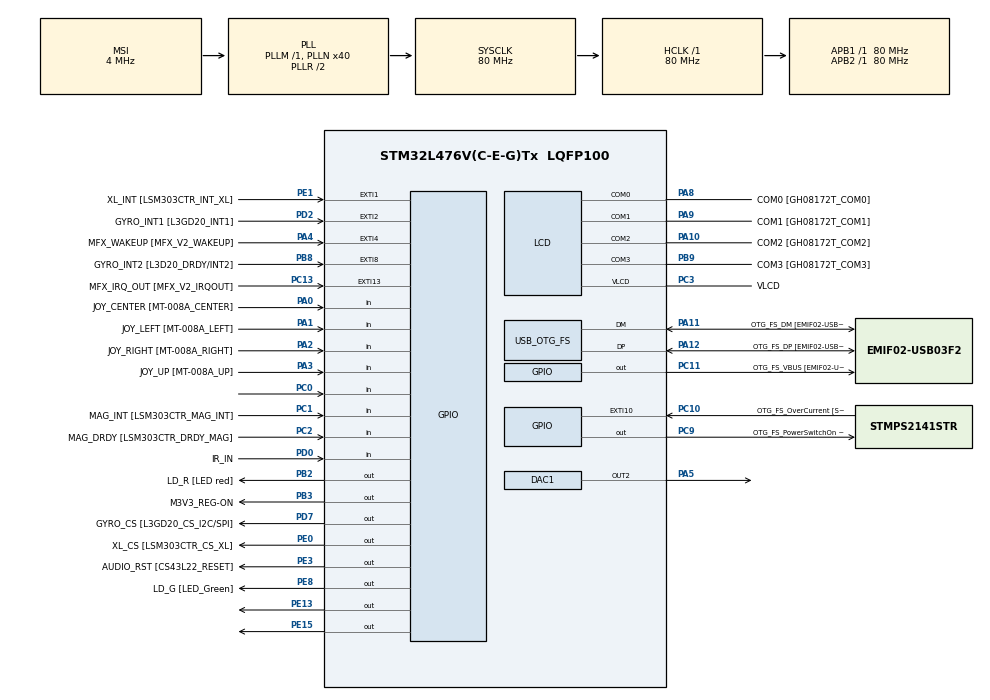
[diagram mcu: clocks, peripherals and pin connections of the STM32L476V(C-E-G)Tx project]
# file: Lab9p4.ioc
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DAC1.DAC_Channel-DAC_OUT2=DAC_CHANNEL_2
Mcu.Family=STM32L4
Mcu.Name=STM32L476V(C-E-G)Tx
Mcu.Package=LQFP100
NVIC.LCD_IRQn=true\:0\:0\:false\:false\:true\:true\:false\:true
NVIC.OTG_FS_IRQn=true\:0\:0\:false\:false\:true\:true\:true\:true
NVIC.PriorityGroup=NVIC_PRIORITYGROUP_4
NVIC.TIM1_UP_TIM16_IRQn=true\:0\:0\:false\:false\:true\:true\:true\:true
NVIC.TIM6_DAC_IRQn=true\:0\:0\:false\:false\:true\:true\:true\:true
NVIC.TIM7_IRQn=true\:0\:0\:false\:false\:true\:true\:true\:true
PA0.GPIO_Label=JOY_CENTER [MT-008A_CENTER]
PA0.GPIO_Mode=GPIO_MODE_INPUT
PA0.GPIO_PuPd=GPIO_PULLDOWN
PA0.Signal=GPIO_Input
PA1.GPIO_Label=JOY_LEFT [MT-008A_LEFT]
PA1.GPIO_Mode=GPIO_MODE_INPUT
PA1.GPIO_PuPd=GPIO_PULLDOWN
PA1.Signal=GPIO_Input
PA10.GPIO_Label=COM2 [GH08172T_COM2]
PA10.GPIO_Mode=GPIO_MODE_AF_PP
PA10.GPIO_PuPd=GPIO_NOPULL
PA10.GPIO_Speed=GPIO_SPEED_FREQ_LOW
PA10.Mode=1/4 Duty Cycle
PA10.Signal=LCD_COM2
PA11.GPIO_Label=OTG_FS_DM [EMIF02-USB03F2_D-out]
PA11.GPIO_Mode=GPIO_MODE_AF_PP
PA11.GPIO_PuPd=GPIO_NOPULL
PA11.GPIO_Speed=GPIO_SPEED_FREQ_VERY_HIGH
PA11.Mode=Host_Only
PA11.Signal=USB_OTG_FS_DM
PA12.GPIO_Label=OTG_FS_DP [EMIF02-USB03F2_D+out]
PA12.GPIO_Mode=GPIO_MODE_AF_PP
PA12.GPIO_PuPd=GPIO_NOPULL
PA12.GPIO_Speed=GPIO_SPEED_FREQ_VERY_HIGH
PA12.Mode=Host_Only
PA12.Signal=USB_OTG_FS_DP
PA13\ (JTMS-SWDIO).GPIO_Label=SWDIO
PA13\ (JTMS-SWDIO).Mode=Serial_Wire
PA13\ (JTMS-SWDIO).Signal=SYS_JTMS-SWDIO
PA14\ (JTCK-SWCLK).GPIO_Label=SWCLK
PA14\ (JTCK-SWCLK).Mode=Serial_Wire
PA14\ (JTCK-SWCLK).Signal=SYS_JTCK-SWCLK
PA15\ (JTDI).GPIO_Label=SEG10 [GH08172T_SEG10]
PA15\ (JTDI).GPIO_Mode=GPIO_MODE_AF_PP
PA15\ (JTDI).GPIO_PuPd=GPIO_NOPULL
PA15\ (JTDI).GPIO_Speed=GPIO_SPEED_FREQ_LOW
PA15\ (JTDI).Signal=LCD_SEG17
PA2.GPIO_Label=JOY_RIGHT [MT-008A_RIGHT]
PA2.GPIO_Mode=GPIO_MODE_INPUT
PA2.GPIO_PuPd=GPIO_PULLDOWN
PA2.Signal=GPIO_Input
PA3.GPIO_Label=JOY_UP [MT-008A_UP]
PA3.GPIO_Mode=GPIO_MODE_INPUT
PA3.GPIO_PuPd=GPIO_PULLDOWN
PA3.Signal=GPIO_Input
PA4.GPIO_Label=MFX_WAKEUP [MFX_V2_WAKEUP]
PA4.GPIO_ModeDefaultEXTI=GPIO_MODE_EVT_RISING
PA4.GPIO_PuPd=GPIO_NOPULL
PA4.Signal=GPXTI4
PA5.Signal=COMP_DAC12_group
PA6.GPIO_Label=SEG23 [GH08172T_SEG23]
PA6.GPIO_Mode=GPIO_MODE_AF_PP
PA6.GPIO_PuPd=GPIO_NOPULL
PA6.GPIO_Speed=GPIO_SPEED_FREQ_LOW
PA6.Signal=LCD_SEG3
PA7.GPIO_Label=SEG0 [GH08172T_SEG0]
PA7.GPIO_Mode=GPIO_MODE_AF_PP
PA7.GPIO_PuPd=GPIO_NOPULL
PA7.GPIO_Speed=GPIO_SPEED_FREQ_LOW
PA7.Signal=LCD_SEG4
PA8.GPIO_Label=COM0 [GH08172T_COM0]
PA8.GPIO_Mode=GPIO_MODE_AF_PP
PA8.GPIO_PuPd=GPIO_NOPULL
PA8.GPIO_Speed=GPIO_SPEED_FREQ_LOW
PA8.Mode=1/4 Duty Cycle
PA8.Signal=LCD_COM0
PA9.GPIO_Label=COM1 [GH08172T_COM1]
PA9.GPIO_Mode=GPIO_MODE_AF_PP
PA9.GPIO_PuPd=GPIO_NOPULL
PA9.GPIO_Speed=GPIO_SPEED_FREQ_LOW
PA9.Mode=1/4 Duty Cycle
PA9.Signal=LCD_COM1
PB0.GPIO_Label=SEG21 [GH08172T_SEG21]
PB0.GPIO_Mode=GPIO_MODE_AF_PP
PB0.GPIO_PuPd=GPIO_NOPULL
PB0.GPIO_Speed=GPIO_SPEED_FREQ_LOW
PB0.Signal=LCD_SEG5
PB1.GPIO_Label=SEG2 [GH08172T_SEG2]
PB1.GPIO_Mode=GPIO_MODE_AF_PP
PB1.GPIO_PuPd=GPIO_NOPULL
PB1.GPIO_Speed=GPIO_SPEED_FREQ_LOW
PB1.Signal=LCD_SEG6
PB10.GPIO_Label=MFX_I2C_SLC [MFX_V2_I2C_SCL]
PB10.GPIO_Mode=GPIO_MODE_AF_OD
PB10.GPIO_PuPdOD=GPIO_PULLUP
PB10.GPIO_Speed=GPIO_SPEED_FREQ_VERY_HIGH
PB10.Signal=I2C2_SCL
PB11.GPIO_Label=MFX_I2C_SDA [MFX_V2_I2C_SDA]
PB11.GPIO_Mode=GPIO_MODE_AF_OD
PB11.GPIO_PuPdOD=GPIO_PULLUP
PB11.GPIO_Speed=GPIO_SPEED_FREQ_VERY_HIGH
PB11.Signal=I2C2_SDA
PB12.GPIO_Label=SEG20 [GH08172T_SEG20]
PB12.GPIO_Mode=GPIO_MODE_AF_PP
PB12.GPIO_PuPd=GPIO_NOPULL
PB12.GPIO_Speed=GPIO_SPEED_FREQ_LOW
PB12.Signal=LCD_SEG12
PB13.GPIO_Label=SEG3 [GH08172T_SEG3]
PB13.GPIO_Mode=GPIO_MODE_AF_PP
PB13.GPIO_PuPd=GPIO_NOPULL
PB13.GPIO_Speed=GPIO_SPEED_FREQ_LOW
PB13.Signal=LCD_SEG13
PB14.GPIO_Label=SEG19 [GH08172T_SEG19]
PB14.GPIO_Mode=GPIO_MODE_AF_PP
PB14.GPIO_PuPd=GPIO_NOPULL
PB14.GPIO_Speed=GPIO_SPEED_FREQ_LOW
PB14.Signal=LCD_SEG14
PB15.GPIO_Label=SEG4 [GH08172T_SEG4]
PB15.GPIO_Mode=GPIO_MODE_AF_PP
PB15.GPIO_PuPd=GPIO_NOPULL
PB15.GPIO_Speed=GPIO_SPEED_FREQ_LOW
PB15.Signal=LCD_SEG15
PB2.GPIO_Label=LD_R [LED red]
PB2.GPIO_ModeDefaultOutputPP=GPIO_MODE_OUTPUT_PP
PB2.GPIO_PuPd=GPIO_PULLUP
PB2.GPIO_Speed=GPIO_SPEED_FREQ_VERY_HIGH
PB2.Signal=GPIO_Output
PB3\ (JTDO-TRACESWO).GPIO_Label=M3V3_REG-ON
PB3\ (JTDO-TRACESWO).GPIO_ModeDefaultOutputPP=GPIO_MODE_OUTPUT_PP
PB3\ (JTDO-TRACESWO).GPIO_PuPd=GPIO_NOPULL
PB3\ (JTDO-TRACESWO).GPIO_Speed=GPIO_SPEED_FREQ_LOW
PB3\ (JTDO-TRACESWO).Signal=GPIO_Output
PB4\ (NJTRST).GPIO_Label=SEG11 [GH08172T_SEG11]
PB4\ (NJTRST).GPIO_Mode=GPIO_MODE_AF_PP
PB4\ (NJTRST).GPIO_PuPd=GPIO_NOPULL
PB4\ (NJTRST).GPIO_Speed=GPIO_SPEED_FREQ_LOW
PB4\ (NJTRST).Signal=LCD_SEG8
PB5.GPIO_Label=SEG12 [GH08172T_SEG12]
PB5.GPIO_Mode=GPIO_MODE_AF_PP
PB5.GPIO_PuPd=GPIO_NOPULL
PB5.GPIO_Speed=GPIO_SPEED_FREQ_LOW
PB5.Signal=LCD_SEG9
PB6.GPIO_FM6=__NULL
PB6.GPIO_Label=I2C1_SCL [SSM-104-L-DH_SCL]
PB6.GPIO_Mode=GPIO_MODE_AF_OD
PB6.GPIO_PuPdOD=GPIO_PULLUP
PB6.GPIO_Speed=GPIO_SPEED_FREQ_VERY_HIGH
PB6.Signal=I2C1_SCL
PB7.GPIO_FM7=__NULL
PB7.GPIO_Label=I2C1_SDA [SSM-104-L-DH_SDA]
PB7.GPIO_Mode=GPIO_MODE_AF_OD
PB7.GPIO_PuPdOD=GPIO_PULLUP
PB7.GPIO_Speed=GPIO_SPEED_FREQ_VERY_HIGH
PB7.Signal=I2C1_SDA
PB8.GPIO_Label=GYRO_INT2 [L3D20_DRDY/INT2]
PB8.GPIO_ModeDefaultEXTI=GPIO_MODE_EVT_RISING
PB8.GPIO_PuPd=GPIO_NOPULL
PB8.Signal=GPXTI8
PB9.GPIO_FM9=__NULL
PB9.GPIO_Label=COM3 [GH08172T_COM3]
PB9.GPIO_Mode=GPIO_MODE_AF_PP
PB9.GPIO_PuPd=GPIO_NOPULL
PB9.GPIO_Speed=GPIO_SPEED_FREQ_LOW
PB9.Mode=1/4 Duty Cycle
PB9.Signal=LCD_COM3
PC0.Signal=GPIO_Input
PC1.GPIO_Label=MAG_INT [LSM303CTR_MAG_INT]
PC1.GPIO_Mode=GPIO_MODE_INPUT
PC1.GPIO_PuPd=GPIO_NOPULL
PC1.Signal=GPIO_Input
PC10.GPIO_Label=OTG_FS_OverCurrent [STMPS2141STR_FAULT]
PC10.GPIO_ModeDefaultEXTI=GPIO_MODE_EVT_RISING
PC10.GPIO_PuPd=GPIO_NOPULL
PC10.Signal=GPXTI10
PC11.GPIO_Label=OTG_FS_VBUS [EMIF02-USB03F2_Vbus]
PC11.GPIO_ModeDefaultOutputPP=GPIO_MODE_OUTPUT_PP
PC11.GPIO_PuPd=GPIO_NOPULL
PC11.GPIO_Speed=GPIO_SPEED_FREQ_LOW
PC11.Signal=GPIO_Output
PC13.GPIO_Label=MFX_IRQ_OUT [MFX_V2_IRQOUT]
PC13.GPIO_ModeDefaultEXTI=GPIO_MODE_EVT_RISING
PC13.GPIO_PuPd=GPIO_NOPULL
PC13.Signal=GPXTI13
PC14-OSC32_IN\ (PC14).Mode=LSE-External-Oscillator
PC14-OSC32_IN\ (PC14).Signal=RCC_OSC32_IN
PC15-OSC32_OUT\ (PC15).Mode=LSE-External-Oscillator
PC15-OSC32_OUT\ (PC15).Signal=RCC_OSC32_OUT
PC2.GPIO_Label=MAG_DRDY [LSM303CTR_DRDY_MAG]
PC2.GPIO_Mode=GPIO_MODE_INPUT
PC2.GPIO_PuPd=GPIO_NOPULL
PC2.Signal=GPIO_Input
PC3.GPIO_Label=VLCD
PC3.GPIO_Mode=GPIO_MODE_AF_PP
PC3.GPIO_PuPd=GPIO_NOPULL
PC3.GPIO_Speed=GPIO_SPEED_FREQ_LOW
PC3.Mode=1/4 Duty Cycle
PC3.Signal=LCD_VLCD
PC4.GPIO_Label=SEG22 [GH08172T_SEG22]
PC4.GPIO_Mode=GPIO_MODE_AF_PP
PC4.GPIO_PuPd=GPIO_NOPULL
PC4.GPIO_Speed=GPIO_SPEED_FREQ_LOW
PC4.Signal=LCD_SEG22
PC5.GPIO_Label=SEG1 [GH08172T_SEG1]
PC5.GPIO_Mode=GPIO_MODE_AF_PP
PC5.GPIO_PuPd=GPIO_NOPULL
PC5.GPIO_Speed=GPIO_SPEED_FREQ_LOW
PC5.Signal=LCD_SEG23
PC6.GPIO_Label=SEG14 [GH08172T_SEG14]
PC6.GPIO_Mode=GPIO_MODE_AF_PP
PC6.GPIO_PuPd=GPIO_NOPULL
PC6.GPIO_Speed=GPIO_SPEED_FREQ_LOW
PC6.Signal=LCD_SEG24
PC7.GPIO_Label=SEG9 [GH08172T_SEG9]
PC7.GPIO_Mode=GPIO_MODE_AF_PP
PC7.GPIO_PuPd=GPIO_NOPULL
PC7.GPIO_Speed=GPIO_SPEED_FREQ_LOW
PC7.Signal=LCD_SEG25
PC8.GPIO_Label=SEG13 [GH08172T_SEG13]
PC8.GPIO_Mode=GPIO_MODE_AF_PP
PC8.GPIO_PuPd=GPIO_NOPULL
PC8.GPIO_Speed=GPIO_SPEED_FREQ_LOW
PC8.Signal=LCD_SEG26
PC9.GPIO_Label=OTG_FS_PowerSwitchOn [STMPS2141STR_EN]
PC9.GPIO_ModeDefaultOutputPP=GPIO_MODE_OUTPUT_PP
PC9.GPIO_PuPd=GPIO_NOPULL
PC9.GPIO_Speed=GPIO_SPEED_FREQ_LOW
PC9.PinState=GPIO_PIN_SET
PC9.Signal=GPIO_Output
PD0.GPIO_Label=IR_IN
PD0.Signal=GPIO_Input
PD1.GPIO_Label=MEMS_SCK [L3GD20_SCL/SPC]
PD1.GPIO_Mode=GPIO_MODE_AF_PP
PD1.GPIO_PuPd=GPIO_NOPULL
PD1.GPIO_Speed=GPIO_SPEED_FREQ_VERY_HIGH
PD1.Signal=SPI2_SCK
PD10.GPIO_Label=SEG17 [GH08172T_SEG17]
PD10.GPIO_Mode=GPIO_MODE_AF_PP
PD10.GPIO_PuPd=GPIO_NOPULL
PD10.GPIO_Speed=GPIO_SPEED_FREQ_LOW
PD10.Signal=LCD_SEG30
PD11.GPIO_Label=SEG6 [GH08172T_SEG6]
PD11.GPIO_Mode=GPIO_MODE_AF_PP
PD11.GPIO_PuPd=GPIO_NOPULL
PD11.GPIO_Speed=GPIO_SPEED_FREQ_LOW
PD11.Signal=LCD_SEG31
PD12.GPIO_Label=SEG16 [GH08172T_SEG16]
PD12.GPIO_Mode=GPIO_MODE_AF_PP
PD12.GPIO_PuPd=GPIO_NOPULL
PD12.GPIO_Speed=GPIO_SPEED_FREQ_LOW
PD12.Signal=LCD_SEG32
PD13.GPIO_Label=SEG7 [GH08172T_SEG7]
PD13.GPIO_Mode=GPIO_MODE_AF_PP
PD13.GPIO_PuPd=GPIO_NOPULL
PD13.GPIO_Speed=GPIO_SPEED_FREQ_LOW
PD13.Signal=LCD_SEG33
PD14.GPIO_Label=SEG15 [GH08172T_SEG15]
PD14.GPIO_Mode=GPIO_MODE_AF_PP
PD14.GPIO_PuPd=GPIO_NOPULL
PD14.GPIO_Speed=GPIO_SPEED_FREQ_LOW
PD14.Signal=LCD_SEG34
PD15.GPIO_Label=SEG8 [GH08172T_SEG8]
PD15.GPIO_Mode=GPIO_MODE_AF_PP
PD15.GPIO_PuPd=GPIO_NOPULL
PD15.GPIO_Speed=GPIO_SPEED_FREQ_LOW
PD15.Signal=LCD_SEG35
PD2.GPIO_Label=GYRO_INT1 [L3GD20_INT1]
PD2.GPIO_ModeDefaultEXTI=GPIO_MODE_EVT_RISING
PD2.GPIO_PuPd=GPIO_NOPULL
PD2.Signal=GPXTI2
PD3.GPIO_Label=MEMS_MISO [L3GD20_SA0/SDO]
PD3.GPIO_Mode=GPIO_MODE_AF_PP
PD3.GPIO_PuPd=GPIO_NOPULL
PD3.GPIO_Speed=GPIO_SPEED_FREQ_VERY_HIGH
PD3.Signal=SPI2_MISO
PD4.GPIO_Label=MEMS_MOSI [L3GD20_SDA/SDI/SDO]
PD4.GPIO_Mode=GPIO_MODE_AF_PP
PD4.GPIO_PuPd=GPIO_NOPULL
PD4.GPIO_Speed=GPIO_SPEED_FREQ_VERY_HIGH
PD4.Signal=SPI2_MOSI
PD5.GPIO_Label=USART_TX
PD5.GPIO_Mode=GPIO_MODE_AF_PP
PD5.GPIO_PuPd=GPIO_PULLUP
PD5.GPIO_Speed=GPIO_SPEED_FREQ_VERY_HIGH
PD5.Signal=USART2_TX
PD6.GPIO_Label=USART_RX
PD6.GPIO_Mode=GPIO_MODE_AF_PP
PD6.GPIO_PuPd=GPIO_PULLUP
PD6.GPIO_Speed=GPIO_SPEED_FREQ_VERY_HIGH
PD6.Signal=USART2_RX
PD7.GPIO_Label=GYRO_CS [L3GD20_CS_I2C/SPI]
PD7.GPIO_ModeDefaultOutputPP=GPIO_MODE_OUTPUT_PP
PD7.GPIO_PuPd=GPIO_NOPULL
PD7.GPIO_Speed=GPIO_SPEED_FREQ_VERY_HIGH
PD7.Signal=GPIO_Output
PD8.GPIO_Label=SEG18 [GH08172T_SEG18]
PD8.GPIO_Mode=GPIO_MODE_AF_PP
PD8.GPIO_PuPd=GPIO_NOPULL
PD8.GPIO_Speed=GPIO_SPEED_FREQ_LOW
PD8.Signal=LCD_SEG28
PD9.GPIO_Label=SEG5 [GH08172T_SEG5]
PD9.GPIO_Mode=GPIO_MODE_AF_PP
PD9.GPIO_PuPd=GPIO_NOPULL
PD9.GPIO_Speed=GPIO_SPEED_FREQ_LOW
PD9.Signal=LCD_SEG29
PE0.GPIO_Label=XL_CS [LSM303CTR_CS_XL]
PE0.GPIO_ModeDefaultOutputPP=GPIO_MODE_OUTPUT_PP
PE0.GPIO_PuPd=GPIO_NOPULL
PE0.GPIO_Speed=GPIO_SPEED_FREQ_LOW
PE0.Signal=GPIO_Output
PE1.GPIO_Label=XL_INT [LSM303CTR_INT_XL]
PE1.GPIO_ModeDefaultEXTI=GPIO_MODE_EVT_RISING
PE1.GPIO_PuPd=GPIO_NOPULL
PE1.Signal=GPXTI1
PE10.GPIO_Label=QSPI_CLK [N25Q128A13EF840E_C]
PE10.GPIO_Mode=GPIO_MODE_AF_PP
PE10.GPIO_PuPd=GPIO_NOPULL
PE10.GPIO_Speed=GPIO_SPEED_FREQ_VERY_HIGH
PE10.Signal=QUADSPI_CLK
PE11.GPIO_Label=QSPI_CS [N25Q128A13EF840E_S\#]
PE11.GPIO_Mode=GPIO_MODE_AF_PP
PE11.GPIO_PuPd=GPIO_NOPULL
PE11.GPIO_Speed=GPIO_SPEED_FREQ_VERY_HIGH
PE11.Signal=QUADSPI_NCS
PE12.GPIO_Label=QSPI_D0 [N25Q128A13EF840E_DQ0]
PE12.GPIO_Mode=GPIO_MODE_AF_PP
PE12.GPIO_PuPd=GPIO_NOPULL
PE12.GPIO_Speed=GPIO_SPEED_FREQ_VERY_HIGH
PE12.Signal=QUADSPI_BK1_IO0
PE13.Signal=GPIO_Output
PE14.GPIO_Label=QSPI_D2 [N25Q128A13EF840E_DQ2]
PE14.GPIO_Mode=GPIO_MODE_AF_PP
PE14.GPIO_PuPd=GPIO_NOPULL
PE14.GPIO_Speed=GPIO_SPEED_FREQ_VERY_HIGH
PE14.Signal=QUADSPI_BK1_IO2
PE15.Signal=GPIO_Output
PE2.GPIO_Label=SAI1_MCK [CS43L22_MCLK]
PE2.GPIO_Mode=GPIO_MODE_AF_PP
PE2.GPIO_PuPd=GPIO_NOPULL
PE2.GPIO_Speed=GPIO_SPEED_FREQ_VERY_HIGH
PE2.Signal=SAI1_MCLK_A
PE3.GPIO_Label=AUDIO_RST [CS43L22_RESET]
PE3.GPIO_ModeDefaultOutputPP=GPIO_MODE_OUTPUT_PP
PE3.GPIO_PuPd=GPIO_NOPULL
PE3.GPIO_Speed=GPIO_SPEED_FREQ_HIGH
PE3.Signal=GPIO_Output
PE4.GPIO_Label=SAI1_FS [CS43L22_LRCK]
PE4.GPIO_Mode=GPIO_MODE_AF_PP
PE4.GPIO_PuPd=GPIO_NOPULL
PE4.GPIO_Speed=GPIO_SPEED_FREQ_VERY_HIGH
PE4.Signal=SAI1_FS_A
PE5.GPIO_Label=SAI1_SCK [CS43L22_SCLK]
PE5.GPIO_Mode=GPIO_MODE_AF_PP
PE5.GPIO_PuPd=GPIO_NOPULL
PE5.GPIO_Speed=GPIO_SPEED_FREQ_VERY_HIGH
PE5.Signal=SAI1_SCK_A
PE6.GPIO_Label=SAI1_SD [CS43L22_SDIN]
PE6.GPIO_Mode=GPIO_MODE_AF_PP
PE6.GPIO_PuPd=GPIO_NOPULL
PE6.GPIO_Speed=GPIO_SPEED_FREQ_VERY_HIGH
PE6.Signal=SAI1_SD_A
PE7.GPIO_Label=AUDIO_DIN [MP34DT01_DOUT]
PE7.GPIO_Mode=GPIO_MODE_AF_PP
PE7.GPIO_PuPd=GPIO_NOPULL
PE7.GPIO_Speed=GPIO_SPEED_FREQ_VERY_HIGH
PE7.Signal=SAI1_SD_B
PE8.GPIO_Label=LD_G [LED_Green]
PE8.GPIO_ModeDefaultOutputPP=GPIO_MODE_OUTPUT_PP
PE8.GPIO_PuPd=GPIO_PULLUP
PE8.GPIO_Speed=GPIO_SPEED_FREQ_VERY_HIGH
PE8.Signal=GPIO_Output
PE9.GPIO_Label=AUDIO_CLK [MP34DT01_CLK]
PE9.GPIO_Mode=GPIO_MODE_AF_PP
PE9.GPIO_PuPd=GPIO_NOPULL
PE9.GPIO_Speed=GPIO_SPEED_FREQ_LOW
PE9.Signal=SAI1_FS_B
PH0-OSC_IN\ (PH0).Mode=HSE-External-Oscillator
PH0-OSC_IN\ (PH0).Signal=RCC_OSC_IN
PH1-OSC_OUT\ (PH1).Mode=HSE-External-Oscillator
PH1-OSC_OUT\ (PH1).Signal=RCC_OSC_OUT
ProjectManager.HeapSize=0x400
ProjectManager.StackSize=0x800
ProjectManager.TargetToolchain=MDK-ARM V5.27
RCC.ADCFreq_Value=48000000
RCC.AHBFreq_Value=80000000
RCC.APB1Freq_Value=80000000
RCC.APB1TimFreq_Value=80000000
RCC.APB2Freq_Value=80000000
RCC.APB2TimFreq_Value=80000000
RCC.CortexFreq_Value=80000000
RCC.HCLKFreq_Value=80000000
RCC.HSE_VALUE=8000000
RCC.HSI_VALUE=16000000
RCC.MSI_VALUE=4000000
RCC.PLLN=40
RCC.PLLSAI1N=24
RCC.PREFETCH_ENABLE=1
RCC.SYSCLKFreq_VALUE=80000000
RCC.SYSCLKSource=RCC_SYSCLKSOURCE_PLLCLK
RCC.USBFreq_Value=48000000
RCC.VCOOutputFreq_Value=160000000
SH.COMP_DAC12_group.0=DAC1_OUT2,DAC_OUT2
TIM16.Period=39999
TIM16.Prescaler=199
TIM6.Period=999
TIM6.Prescaler=4
TIM6.TIM_MasterOutputTrigger=TIM_TRGO_UPDATE
TIM7.Period=79
TIM7.Prescaler=99
USB_HOST.BSP.number=1
USB_HOST.USBH_HandleTypeDef=hUsbHostFS
USB_HOST.VirtualModeFS=Msc
USB_HOST0.BSP.STBoard=false
USB_HOST0.BSP.api=Unknown
USB_HOST0.BSP.instance=PC9
USB_HOST0.BSP.ip=GPIO
USB_HOST0.BSP.mode=Output
USB_HOST0.BSP.name=Drive_VBUS_FS
USB_HOST0.BSP.solution=PC9
USB_OTG_FS.VirtualMode=Host_Only
USB_OTG_FS.phy_itface=HCD_PHY_EMBEDDED
VP_FATFS_VS_USB.Mode=USB
VP_RTC_VS_RTC_Activate.Mode=RTC_Enabled
VP_TIM16_VS_ClockSourceINT.Mode=Enable_Timer
VP_TIM6_VS_ClockSourceINT.Mode=Enable_Timer
VP_TIM7_VS_ClockSourceINT.Mode=Enable_Timer
VP_USB_HOST_VS_USB_HOST_MSC_FS.Mode=MSC_FS
board=STM32L476G-DISCO

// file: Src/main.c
/* USER CODE BEGIN Header */
/**
  ******************************************************************************
  * @file           : main.c
  * @brief          : Main program body
  ******************************************************************************
  * @attention
  *
  * <h2><center>&copy; Copyright (c) 2020 STMicroelectronics.
  * All rights reserved.</center></h2>
  *
  * This software component is licensed by ST under Ultimate Liberty license
  * SLA0044, the "License"; You may not use this file except in compliance with
  * the License. You may obtain a copy of the License at:
  *                             www.st.com/SLA0044
  *
  ******************************************************************************
  */
/* USER CODE END Header */
#include "main.h"
#include "fatfs.h"
#include "usb_host.h"

/* USER CODE BEGIN Includes */
#include <stdbool.h>
#include "song16.h"
#include "stm32l476g_discovery.h"
#include "stm32l476g_discovery_glass_lcd.h"
#include "display.h"

/* USER CODE END Includes */

DAC_HandleTypeDef hdac1;

LCD_HandleTypeDef hlcd;

RTC_HandleTypeDef hrtc;

TIM_HandleTypeDef htim6;
TIM_HandleTypeDef htim7;
TIM_HandleTypeDef htim16;

/* USER CODE BEGIN PV */

extern ApplicationTypeDef Appli_state;

int16_t audiobuffer[NUM_ABUF][ABUF_SIZE]; 	/* File read buffer for audio */
volatile bool abuf_full[NUM_ABUF];
bool file_open = false;
int fill_buf = 0;
int lastbuffer = 0;
volatile uint8_t volume = DFLT_VOLUME;		// Volume range is 0 to 255
uint8_t noisehigh[8] = {0xff, 0xdd, 0xbb, 0x99, 0x77, 0x55, 0x33, 0x11};

char *rfilename = "songfile.raw";
volatile unsigned int irdat[SAMPLE_COUNT];
unsigned int z;
extern int IrFlag;
extern int flag;
int temp;
extern int volume2;
uint8_t ch0 = 3;
extern volatile int seccount;
extern volatile int tenseccount;
extern volatile int tenmincount;
extern volatile int mincount;
extern volatile int tenth;
int index;
extern int k;
extern int j;
extern int i;
extern int count;
#define IR_A 0x00ff22dd
#define IR_B 0x00ff02fd
#define IR_C 0x00ffc23d
#define IR_POWER 0x00ff629d
#define IR_UP 0x00ff9867
#define IR_DOWN 0x00ff38c7
#define IR_LEFT 0x00ff30cf
#define IR_RIGHT 0x00ff7a85
#define IR_CIRCLE 0x00ff18e7

FIL MyFile;                   /* File object */

/* USER CODE END PV */

void SystemClock_Config(void);
static void MX_GPIO_Init(void);
static void MX_DAC1_Init(void);
static void MX_TIM6_Init(void);
static void MX_RTC_Init(void);
static void MX_LCD_Init(void);
static void MX_TIM16_Init(void);
static void MX_TIM7_Init(void);
void MX_USB_HOST_Process(void);

/* USER CODE BEGIN 0 */

static void FS_FileOpen(void) {

	 /* Register the file system object to the FatFs module */
  if(f_mount(&USBHFatFS, (TCHAR const*)USBHPath, 0) == FR_OK) {
		/* Open the text file object with read access */
		if(f_open(&MyFile, rfilename, FA_READ) == FR_OK) {
			HAL_GPIO_WritePin(LD_G_GPIO_Port, LD_G_Pin,GPIO_PIN_SET);
			file_open = true;
			return;
		}
	}
			HAL_GPIO_WritePin(LD_R_GPIO_Port, LD_R_Pin,GPIO_PIN_SET);
}

static void FS_FileClose(void) {
	/* Close the open text file */
	f_close(&MyFile);
	file_open = false;
}

static void FS_FileRead(uint8_t *abuffer) {
	FRESULT res;                            /* FatFs function common result code */
  uint32_t bytesread;                     /* File write/read counts */

	 			/* Read data from the 16-bit raw file if the next buffer is free */
	res = f_read(&MyFile, abuffer, ABUF_BYTE_SIZE, (void *)&bytesread);
	if((bytesread < ABUF_BYTE_SIZE) && (res == FR_OK)) {
		lastbuffer = bytesread;
		for (int i = bytesread/2; i<ABUF_BYTE_SIZE/2; i++) {
			abuffer[i+i+1] = noisehigh[i%8];
			abuffer[i+i] = 0;
		}
	}
}

void write_DAC1Ch2(int16_t dacval, uint8_t volume) {
	int tempval;
	tempval = (((int) dacval * (int) volume) + 8388608) >> 12;
	hdac1.Instance->DHR12R2 = tempval;
}

uint32_t parseIRCode()
	{
    uint32_t num = 0;
		int count = 0;
		int arrayCount = 0;
		uint32_t mask = 0x80000000;
		/*skips header */
		while(irdat[arrayCount] !=0)
		{
			arrayCount++;
		}
		while(irdat[arrayCount] !=1)
		{
			arrayCount++;
		}
		/* skips header */
		while(arrayCount != SAMPLE_COUNT)
		{
			if(irdat[arrayCount] ==0)
			{
				count++;
			}
			else
			{
				if(count < 8 && count !=0)
				{
					mask/=2;
				}
				else if(count > 8 && count != 0)
				{
					num |= mask;
					mask/=2;
				}
				count = 0;
			}
			arrayCount++;
		}
		return num;
	}

/* USER CODE END 0 */

int main(void)
{

  /* MCU Configuration--------------------------------------------------------*/

  /* Reset of all peripherals, Initializes the Flash interface and the Systick. */
  HAL_Init();

  /* Configure the system clock */
  SystemClock_Config();

  /* Initialize all configured peripherals */
  MX_GPIO_Init();
  MX_USB_HOST_Init();
  MX_FATFS_Init();
  MX_DAC1_Init();
  MX_TIM6_Init();
  MX_RTC_Init();
  MX_LCD_Init();
  MX_TIM16_Init();
  MX_TIM7_Init();
  /* USER CODE BEGIN 2 */

	/* initialize data structures */

	for (int i=0; i<NUM_ABUF; i++) {
		abuf_full[i] = false;
	}
	/* start devices */

  HAL_DAC_Start(&hdac1, DAC1_CHANNEL_2);
	HAL_TIM_Base_Start_IT(&htim6);			/* Start Timer 6 at 16KHz to run DAC */
	HAL_TIM_Base_Start_IT(&htim16);
	HAL_TIM_Base_Start_IT(&htim7);
	BSP_LCD_GLASS_Init();
	BSP_LCD_GLASS_Clear();
	uint8_t x = 48;//set up all zeroes
	BSP_LCD_GLASS_DisplayChar(&x, POINT_OFF, DOUBLEPOINT_OFF , 5);
	BSP_LCD_GLASS_DisplayChar(&x, POINT_OFF, DOUBLEPOINT_OFF , 4);
	BSP_LCD_GLASS_DisplayChar(&x, POINT_OFF, DOUBLEPOINT_ON , 3);
	BSP_LCD_GLASS_DisplayChar(&x, POINT_OFF, DOUBLEPOINT_OFF , 2);
	BSP_LCD_GLASS_BarLevelConfig(ch0);

  /* USER CODE END 2 */

  /* Infinite loop */
  while (1)
  {
    MX_USB_HOST_Process();

    /* USER CODE BEGIN 3 */
    /* Mass Storage Application State Machine */
		if(IrFlag == 1)
		{
			uint32_t num = parseIRCode();
			if(num == IR_A)
			{

			}
			if(num == IR_B)
			{

			}
			if(num == IR_C)
			{

			}
			if(num == IR_POWER)
			{

			}

			if(num == IR_UP)
			{
				if(volume2+VOLUME_INCREMENT < 255)
				{
					volume2 += VOLUME_INCREMENT;
				}
				if(volume2 > 190)
				{
					ch0=4;
				}
				if(volume2 > 130 && volume2 <= 190)
				{
					ch0=3;
				}
				if(volume2 <= 130 && volume2 > 70)
				{
					ch0=2;
				}
				if(volume2 <=70)
				{
					ch0 = 1;
				}
			}

			if(num == IR_DOWN)
			{
				if(volume2-VOLUME_INCREMENT > 0)
				{
					volume2 -= VOLUME_INCREMENT;
				}
				if(volume2 > 190)
				{
					ch0=4;
				}
				if(volume2 > 130 && volume2 <= 190)
				{
					ch0=3;
				}
				if(volume2 <= 130 && volume2 > 70)
				{
					ch0=2;
				}
				if(volume2 <=70)
				{
					ch0 = 1;
				}
			}

			if(num == IR_LEFT)
			{
				abuf_full[0] = true;
				abuf_full[1] = true;
				for(index=0; index < ABUF_SIZE; index++)
				{
					audiobuffer[0][index] = 0;
					audiobuffer[1][index] = 0;
				}
				if(flag == 2)
				{
					flag = 0;
					Appli_state = APPLICATION_READY;
					count = 0;
					k=0;
				}
				i=0;
				j=0;
				abuf_full[0] = false;
				abuf_full[1] = false;
				fill_buf = 0;
				lastbuffer = 0;
				FS_FileClose();
				file_open = false;
				BSP_LCD_GLASS_Clear();
				x = 48;//set up all zeroes
				seccount = 0;
				tenseccount = 0;
				tenmincount = 0;
				mincount = 0;
				tenth = 0;
				BSP_LCD_GLASS_DisplayChar(&x, POINT_OFF, DOUBLEPOINT_OFF , 5);
				BSP_LCD_GLASS_DisplayChar(&x, POINT_OFF, DOUBLEPOINT_OFF , 4);
				BSP_LCD_GLASS_DisplayChar(&x, POINT_OFF, DOUBLEPOINT_ON , 3);
				BSP_LCD_GLASS_DisplayChar(&x, POINT_OFF, DOUBLEPOINT_OFF , 2);
				BSP_LCD_GLASS_BarLevelConfig(ch0);

			}
			if(num == IR_RIGHT)
			{

			}
			if(num == IR_CIRCLE)
			{
				//HAL_GPIO_TogglePin(LD_G_GPIO_Port, LD_G_Pin);
				if(flag == 2)
				{
					flag = temp;
				}
				else
				{
					temp = flag;
					flag = 2;
				}
			}
			IrFlag=0;
		}
    switch(Appli_state) {
      case APPLICATION_READY:
        if (!file_open) FS_FileOpen();
			  if (file_open && (lastbuffer == 0)) {
					if (!abuf_full[fill_buf]) {
						FS_FileRead((uint8_t *) audiobuffer[fill_buf]);
						abuf_full[fill_buf++] = true;
						fill_buf = fill_buf % NUM_ABUF;
					}
				}
				if (file_open && (lastbuffer != 0)) {
					FS_FileClose();
          Appli_state = APPLICATION_IDLE;
				}
        break;

      case APPLICATION_IDLE:
        default:
        break;
      }

		}
  /* USER CODE END 3 */
}

void SystemClock_Config(void)
{
  RCC_OscInitTypeDef RCC_OscInitStruct = {0};
  RCC_ClkInitTypeDef RCC_ClkInitStruct = {0};

  /** Configure the main internal regulator output voltage
  */
  if (HAL_PWREx_ControlVoltageScaling(PWR_REGULATOR_VOLTAGE_SCALE1) != HAL_OK)
  {
    Error_Handler();
  }

  /** Configure LSE Drive Capability
  */
  HAL_PWR_EnableBkUpAccess();
  __HAL_RCC_LSEDRIVE_CONFIG(RCC_LSEDRIVE_LOW);

  /** Initializes the RCC Oscillators according to the specified parameters
  * in the RCC_OscInitTypeDef structure.
  */
  RCC_OscInitStruct.OscillatorType = RCC_OSCILLATORTYPE_LSI|RCC_OSCILLATORTYPE_LSE
                              |RCC_OSCILLATORTYPE_MSI;
  RCC_OscInitStruct.LSEState = RCC_LSE_ON;
  RCC_OscInitStruct.LSIState = RCC_LSI_ON;
  RCC_OscInitStruct.MSIState = RCC_MSI_ON;
  RCC_OscInitStruct.MSICalibrationValue = 0;
  RCC_OscInitStruct.MSIClockRange = RCC_MSIRANGE_6;
  RCC_OscInitStruct.PLL.PLLState = RCC_PLL_ON;
  RCC_OscInitStruct.PLL.PLLSource = RCC_PLLSOURCE_MSI;
  RCC_OscInitStruct.PLL.PLLM = 1;
  RCC_OscInitStruct.PLL.PLLN = 40;
  RCC_OscInitStruct.PLL.PLLP = RCC_PLLP_DIV7;
  RCC_OscInitStruct.PLL.PLLQ = RCC_PLLQ_DIV2;
  RCC_OscInitStruct.PLL.PLLR = RCC_PLLR_DIV2;
  if (HAL_RCC_OscConfig(&RCC_OscInitStruct) != HAL_OK)
  {
    Error_Handler();
  }

  /** Initializes the CPU, AHB and APB buses clocks
  */
  RCC_ClkInitStruct.ClockType = RCC_CLOCKTYPE_HCLK|RCC_CLOCKTYPE_SYSCLK
                              |RCC_CLOCKTYPE_PCLK1|RCC_CLOCKTYPE_PCLK2;
  RCC_ClkInitStruct.SYSCLKSource = RCC_SYSCLKSOURCE_PLLCLK;
  RCC_ClkInitStruct.AHBCLKDivider = RCC_SYSCLK_DIV1;
  RCC_ClkInitStruct.APB1CLKDivider = RCC_HCLK_DIV1;
  RCC_ClkInitStruct.APB2CLKDivider = RCC_HCLK_DIV1;

  if (HAL_RCC_ClockConfig(&RCC_ClkInitStruct, FLASH_LATENCY_4) != HAL_OK)
  {
    Error_Handler();
  }

  /** Enable MSI Auto calibration
  */
  HAL_RCCEx_EnableMSIPLLMode();
}

static void MX_DAC1_Init(void)
{

  DAC_ChannelConfTypeDef sConfig = {0};

  /** DAC Initialization
  */
  hdac1.Instance = DAC1;
  if (HAL_DAC_Init(&hdac1) != HAL_OK)
  {
    Error_Handler();
  }

  /** DAC channel OUT2 config
  */
  sConfig.DAC_SampleAndHold = DAC_SAMPLEANDHOLD_DISABLE;
  sConfig.DAC_Trigger = DAC_TRIGGER_NONE;
  sConfig.DAC_OutputBuffer = DAC_OUTPUTBUFFER_ENABLE;
  sConfig.DAC_ConnectOnChipPeripheral = DAC_CHIPCONNECT_DISABLE;
  sConfig.DAC_UserTrimming = DAC_TRIMMING_FACTORY;
  if (HAL_DAC_ConfigChannel(&hdac1, &sConfig, DAC_CHANNEL_2) != HAL_OK)
  {
    Error_Handler();
  }

}

static void MX_LCD_Init(void)
{

  hlcd.Instance = LCD;
  hlcd.Init.Prescaler = LCD_PRESCALER_1;
  hlcd.Init.Divider = LCD_DIVIDER_16;
  hlcd.Init.Duty = LCD_DUTY_1_4;
  hlcd.Init.Bias = LCD_BIAS_1_4;
  hlcd.Init.VoltageSource = LCD_VOLTAGESOURCE_INTERNAL;
  hlcd.Init.Contrast = LCD_CONTRASTLEVEL_0;
  hlcd.Init.DeadTime = LCD_DEADTIME_0;
  hlcd.Init.PulseOnDuration = LCD_PULSEONDURATION_0;
  hlcd.Init.MuxSegment = LCD_MUXSEGMENT_DISABLE;
  hlcd.Init.BlinkMode = LCD_BLINKMODE_OFF;
  hlcd.Init.BlinkFrequency = LCD_BLINKFREQUENCY_DIV8;
  hlcd.Init.HighDrive = LCD_HIGHDRIVE_DISABLE;
  if (HAL_LCD_Init(&hlcd) != HAL_OK)
  {
    Error_Handler();
  }

}

static void MX_RTC_Init(void)
{

  /** Initialize RTC Only
  */
  hrtc.Instance = RTC;
  hrtc.Init.HourFormat = RTC_HOURFORMAT_24;
  hrtc.Init.AsynchPrediv = 127;
  hrtc.Init.SynchPrediv = 255;
  hrtc.Init.OutPut = RTC_OUTPUT_DISABLE;
  hrtc.Init.OutPutRemap = RTC_OUTPUT_REMAP_NONE;
  hrtc.Init.OutPutPolarity = RTC_OUTPUT_POLARITY_HIGH;
  hrtc.Init.OutPutType = RTC_OUTPUT_TYPE_OPENDRAIN;
  if (HAL_RTC_Init(&hrtc) != HAL_OK)
  {
    Error_Handler();
  }

}

static void MX_TIM6_Init(void)
{

  TIM_MasterConfigTypeDef sMasterConfig = {0};

  htim6.Instance = TIM6;
  htim6.Init.Prescaler = 4;
  htim6.Init.CounterMode = TIM_COUNTERMODE_UP;
  htim6.Init.Period = 999;
  htim6.Init.AutoReloadPreload = TIM_AUTORELOAD_PRELOAD_DISABLE;
  if (HAL_TIM_Base_Init(&htim6) != HAL_OK)
  {
    Error_Handler();
  }
  sMasterConfig.MasterOutputTrigger = TIM_TRGO_UPDATE;
  sMasterConfig.MasterSlaveMode = TIM_MASTERSLAVEMODE_DISABLE;
  if (HAL_TIMEx_MasterConfigSynchronization(&htim6, &sMasterConfig) != HAL_OK)
  {
    Error_Handler();
  }

}

static void MX_TIM7_Init(void)
{

  TIM_MasterConfigTypeDef sMasterConfig = {0};

  htim7.Instance = TIM7;
  htim7.Init.Prescaler = 99;
  htim7.Init.CounterMode = TIM_COUNTERMODE_UP;
  htim7.Init.Period = 79;
  htim7.Init.AutoReloadPreload = TIM_AUTORELOAD_PRELOAD_DISABLE;
  if (HAL_TIM_Base_Init(&htim7) != HAL_OK)
  {
    Error_Handler();
  }
  sMasterConfig.MasterOutputTrigger = TIM_TRGO_RESET;
  sMasterConfig.MasterSlaveMode = TIM_MASTERSLAVEMODE_DISABLE;
  if (HAL_TIMEx_MasterConfigSynchronization(&htim7, &sMasterConfig) != HAL_OK)
  {
    Error_Handler();
  }

}

static void MX_TIM16_Init(void)
{

  htim16.Instance = TIM16;
  htim16.Init.Prescaler = 199;
  htim16.Init.CounterMode = TIM_COUNTERMODE_UP;
  htim16.Init.Period = 39999;
  htim16.Init.ClockDivision = TIM_CLOCKDIVISION_DIV1;
  htim16.Init.RepetitionCounter = 0;
  htim16.Init.AutoReloadPreload = TIM_AUTORELOAD_PRELOAD_DISABLE;
  if (HAL_TIM_Base_Init(&htim16) != HAL_OK)
  {
    Error_Handler();
  }

}

static void MX_GPIO_Init(void)
{
  GPIO_InitTypeDef GPIO_InitStruct = {0};

  /* GPIO Ports Clock Enable */
  __HAL_RCC_GPIOE_CLK_ENABLE();
  __HAL_RCC_GPIOC_CLK_ENABLE();
  __HAL_RCC_GPIOH_CLK_ENABLE();
  __HAL_RCC_GPIOA_CLK_ENABLE();
  __HAL_RCC_GPIOB_CLK_ENABLE();
  __HAL_RCC_GPIOD_CLK_ENABLE();

  /*Configure GPIO pin Output Level */
  HAL_GPIO_WritePin(GPIOE, AUDIO_RST_Pin|LD_G_Pin|XL_CS_Pin, GPIO_PIN_RESET);

  /*Configure GPIO pin Output Level */
  HAL_GPIO_WritePin(GPIOB, LD_R_Pin|M3V3_REG_ON_Pin, GPIO_PIN_RESET);

  /*Configure GPIO pin Output Level */
  HAL_GPIO_WritePin(OTG_FS_PowerSwitchOn_GPIO_Port, OTG_FS_PowerSwitchOn_Pin, GPIO_PIN_SET);

  /*Configure GPIO pin Output Level */
  HAL_GPIO_WritePin(OTG_FS_VBUS_GPIO_Port, OTG_FS_VBUS_Pin, GPIO_PIN_RESET);

  /*Configure GPIO pin Output Level */
  HAL_GPIO_WritePin(GYRO_CS_GPIO_Port, GYRO_CS_Pin, GPIO_PIN_RESET);

  /*Configure GPIO pins : SAI1_MCK_Pin SAI1_FS_Pin SAI1_SCK_Pin SAI1_SD_Pin
                           AUDIO_DIN_Pin */
  GPIO_InitStruct.Pin = SAI1_MCK_Pin|SAI1_FS_Pin|SAI1_SCK_Pin|SAI1_SD_Pin
                          |AUDIO_DIN_Pin;
  GPIO_InitStruct.Mode = GPIO_MODE_AF_PP;
  GPIO_InitStruct.Pull = GPIO_NOPULL;
  GPIO_InitStruct.Speed = GPIO_SPEED_FREQ_VERY_HIGH;
  GPIO_InitStruct.Alternate = GPIO_AF13_SAI1;
  HAL_GPIO_Init(GPIOE, &GPIO_InitStruct);

  /*Configure GPIO pin : AUDIO_RST_Pin */
  GPIO_InitStruct.Pin = AUDIO_RST_Pin;
  GPIO_InitStruct.Mode = GPIO_MODE_OUTPUT_PP;
  GPIO_InitStruct.Pull = GPIO_NOPULL;
  GPIO_InitStruct.Speed = GPIO_SPEED_FREQ_HIGH;
  HAL_GPIO_Init(AUDIO_RST_GPIO_Port, &GPIO_InitStruct);

  /*Configure GPIO pins : MFX_IRQ_OUT_Pin OTG_FS_OverCurrent_Pin */
  GPIO_InitStruct.Pin = MFX_IRQ_OUT_Pin|OTG_FS_OverCurrent_Pin;
  GPIO_InitStruct.Mode = GPIO_MODE_EVT_RISING;
  GPIO_InitStruct.Pull = GPIO_NOPULL;
  HAL_GPIO_Init(GPIOC, &GPIO_InitStruct);

  /*Configure GPIO pins : PC0 MAG_INT_Pin MAG_DRDY_Pin */
  GPIO_InitStruct.Pin = GPIO_PIN_0|MAG_INT_Pin|MAG_DRDY_Pin;
  GPIO_InitStruct.Mode = GPIO_MODE_INPUT;
  GPIO_InitStruct.Pull = GPIO_NOPULL;
  HAL_GPIO_Init(GPIOC, &GPIO_InitStruct);

  /*Configure GPIO pins : JOY_CENTER_Pin JOY_LEFT_Pin JOY_RIGHT_Pin JOY_UP_Pin */
  GPIO_InitStruct.Pin = JOY_CENTER_Pin|JOY_LEFT_Pin|JOY_RIGHT_Pin|JOY_UP_Pin;
  GPIO_InitStruct.Mode = GPIO_MODE_INPUT;
  GPIO_InitStruct.Pull = GPIO_PULLDOWN;
  HAL_GPIO_Init(GPIOA, &GPIO_InitStruct);

  /*Configure GPIO pin : MFX_WAKEUP_Pin */
  GPIO_InitStruct.Pin = MFX_WAKEUP_Pin;
  GPIO_InitStruct.Mode = GPIO_MODE_EVT_RISING;
  GPIO_InitStruct.Pull = GPIO_NOPULL;
  HAL_GPIO_Init(MFX_WAKEUP_GPIO_Port, &GPIO_InitStruct);

  /*Configure GPIO pin : LD_R_Pin */
  GPIO_InitStruct.Pin = LD_R_Pin;
  GPIO_InitStruct.Mode = GPIO_MODE_OUTPUT_PP;
  GPIO_InitStruct.Pull = GPIO_PULLUP;
  GPIO_InitStruct.Speed = GPIO_SPEED_FREQ_VERY_HIGH;
  HAL_GPIO_Init(LD_R_GPIO_Port, &GPIO_InitStruct);

  /*Configure GPIO pin : LD_G_Pin */
  GPIO_InitStruct.Pin = LD_G_Pin;
  GPIO_InitStruct.Mode = GPIO_MODE_OUTPUT_PP;
  GPIO_InitStruct.Pull = GPIO_PULLUP;
  GPIO_InitStruct.Speed = GPIO_SPEED_FREQ_VERY_HIGH;
  HAL_GPIO_Init(LD_G_GPIO_Port, &GPIO_InitStruct);

  /*Configure GPIO pin : AUDIO_CLK_Pin */
  GPIO_InitStruct.Pin = AUDIO_CLK_Pin;
  GPIO_InitStruct.Mode = GPIO_MODE_AF_PP;
  GPIO_InitStruct.Pull = GPIO_NOPULL;
  GPIO_InitStruct.Speed = GPIO_SPEED_FREQ_LOW;
  GPIO_InitStruct.Alternate = GPIO_AF13_SAI1;
  HAL_GPIO_Init(AUDIO_CLK_GPIO_Port, &GPIO_InitStruct);

  /*Configure GPIO pins : QSPI_CLK_Pin QSPI_CS_Pin QSPI_D0_Pin QSPI_D1_Pin
                           QSPI_D2_Pin QSPI_D3_Pin */
  GPIO_InitStruct.Pin = QSPI_CLK_Pin|QSPI_CS_Pin|QSPI_D0_Pin|QSPI_D1_Pin
                          |QSPI_D2_Pin|QSPI_D3_Pin;
  GPIO_InitStruct.Mode = GPIO_MODE_AF_PP;
  GPIO_InitStruct.Pull = GPIO_NOPULL;
  GPIO_InitStruct.Speed = GPIO_SPEED_FREQ_VERY_HIGH;
  GPIO_InitStruct.Alternate = GPIO_AF10_QUADSPI;
  HAL_GPIO_Init(GPIOE, &GPIO_InitStruct);

  /*Configure GPIO pins : MFX_I2C_SLC_Pin MFX_I2C_SDA_Pin */
  GPIO_InitStruct.Pin = MFX_I2C_SLC_Pin|MFX_I2C_SDA_Pin;
  GPIO_InitStruct.Mode = GPIO_MODE_AF_OD;
  GPIO_InitStruct.Pull = GPIO_NOPULL;
  GPIO_InitStruct.Speed = GPIO_SPEED_FREQ_VERY_HIGH;
  GPIO_InitStruct.Alternate = GPIO_AF4_I2C2;
  HAL_GPIO_Init(GPIOB, &GPIO_InitStruct);

  /*Configure GPIO pins : OTG_FS_PowerSwitchOn_Pin OTG_FS_VBUS_Pin */
  GPIO_InitStruct.Pin = OTG_FS_PowerSwitchOn_Pin|OTG_FS_VBUS_Pin;
  GPIO_InitStruct.Mode = GPIO_MODE_OUTPUT_PP;
  GPIO_InitStruct.Pull = GPIO_NOPULL;
  GPIO_InitStruct.Speed = GPIO_SPEED_FREQ_LOW;
  HAL_GPIO_Init(GPIOC, &GPIO_InitStruct);

  /*Configure GPIO pin : IR_IN_Pin */
  GPIO_InitStruct.Pin = IR_IN_Pin;
  GPIO_InitStruct.Mode = GPIO_MODE_INPUT;
  GPIO_InitStruct.Pull = GPIO_NOPULL;
  HAL_GPIO_Init(IR_IN_GPIO_Port, &GPIO_InitStruct);

  /*Configure GPIO pins : MEMS_SCK_Pin MEMS_MISO_Pin MEMS_MOSI_Pin */
  GPIO_InitStruct.Pin = MEMS_SCK_Pin|MEMS_MISO_Pin|MEMS_MOSI_Pin;
  GPIO_InitStruct.Mode = GPIO_MODE_AF_PP;
  GPIO_InitStruct.Pull = GPIO_NOPULL;
  GPIO_InitStruct.Speed = GPIO_SPEED_FREQ_VERY_HIGH;
  GPIO_InitStruct.Alternate = GPIO_AF5_SPI2;
  HAL_GPIO_Init(GPIOD, &GPIO_InitStruct);

  /*Configure GPIO pin : GYRO_INT1_Pin */
  GPIO_InitStruct.Pin = GYRO_INT1_Pin;
  GPIO_InitStruct.Mode = GPIO_MODE_EVT_RISING;
  GPIO_InitStruct.Pull = GPIO_NOPULL;
  HAL_GPIO_Init(GYRO_INT1_GPIO_Port, &GPIO_InitStruct);

  /*Configure GPIO pins : USART_TX_Pin USART_RX_Pin */
  GPIO_InitStruct.Pin = USART_TX_Pin|USART_RX_Pin;
  GPIO_InitStruct.Mode = GPIO_MODE_AF_PP;
  GPIO_InitStruct.Pull = GPIO_PULLUP;
  GPIO_InitStruct.Speed = GPIO_SPEED_FREQ_VERY_HIGH;
  GPIO_InitStruct.Alternate = GPIO_AF7_USART2;
  HAL_GPIO_Init(GPIOD, &GPIO_InitStruct);

  /*Configure GPIO pin : GYRO_CS_Pin */
  GPIO_InitStruct.Pin = GYRO_CS_Pin;
  GPIO_InitStruct.Mode = GPIO_MODE_OUTPUT_PP;
  GPIO_InitStruct.Pull = GPIO_NOPULL;
  GPIO_InitStruct.Speed = GPIO_SPEED_FREQ_VERY_HIGH;
  HAL_GPIO_Init(GYRO_CS_GPIO_Port, &GPIO_InitStruct);

  /*Configure GPIO pin : M3V3_REG_ON_Pin */
  GPIO_InitStruct.Pin = M3V3_REG_ON_Pin;
  GPIO_InitStruct.Mode = GPIO_MODE_OUTPUT_PP;
  GPIO_InitStruct.Pull = GPIO_NOPULL;
  GPIO_InitStruct.Speed = GPIO_SPEED_FREQ_LOW;
  HAL_GPIO_Init(M3V3_REG_ON_GPIO_Port, &GPIO_InitStruct);

  /*Configure GPIO pins : I2C1_SCL_Pin I2C1_SDA_Pin */
  GPIO_InitStruct.Pin = I2C1_SCL_Pin|I2C1_SDA_Pin;
  GPIO_InitStruct.Mode = GPIO_MODE_AF_OD;
  GPIO_InitStruct.Pull = GPIO_NOPULL;
  GPIO_InitStruct.Speed = GPIO_SPEED_FREQ_VERY_HIGH;
  GPIO_InitStruct.Alternate = GPIO_AF4_I2C1;
  HAL_GPIO_Init(GPIOB, &GPIO_InitStruct);

  /*Configure GPIO pin : GYRO_INT2_Pin */
  GPIO_InitStruct.Pin = GYRO_INT2_Pin;
  GPIO_InitStruct.Mode = GPIO_MODE_EVT_RISING;
  GPIO_InitStruct.Pull = GPIO_NOPULL;
  HAL_GPIO_Init(GYRO_INT2_GPIO_Port, &GPIO_InitStruct);

  /*Configure GPIO pin : XL_CS_Pin */
  GPIO_InitStruct.Pin = XL_CS_Pin;
  GPIO_InitStruct.Mode = GPIO_MODE_OUTPUT_PP;
  GPIO_InitStruct.Pull = GPIO_NOPULL;
  GPIO_InitStruct.Speed = GPIO_SPEED_FREQ_LOW;
  HAL_GPIO_Init(XL_CS_GPIO_Port, &GPIO_InitStruct);

  /*Configure GPIO pin : XL_INT_Pin */
  GPIO_InitStruct.Pin = XL_INT_Pin;
  GPIO_InitStruct.Mode = GPIO_MODE_EVT_RISING;
  GPIO_InitStruct.Pull = GPIO_NOPULL;
  HAL_GPIO_Init(XL_INT_GPIO_Port, &GPIO_InitStruct);

}

void Error_Handler(void)
{
}
